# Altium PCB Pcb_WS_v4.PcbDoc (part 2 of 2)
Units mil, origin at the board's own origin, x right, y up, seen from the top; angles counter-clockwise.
Board outline 3890 x 3890 mil, 2 copper layers (Top Layer, Bottom Layer); 84 components, 65 nets, 260 pads, 399 vias.
Unrouted connection lines stored in the file: 15.

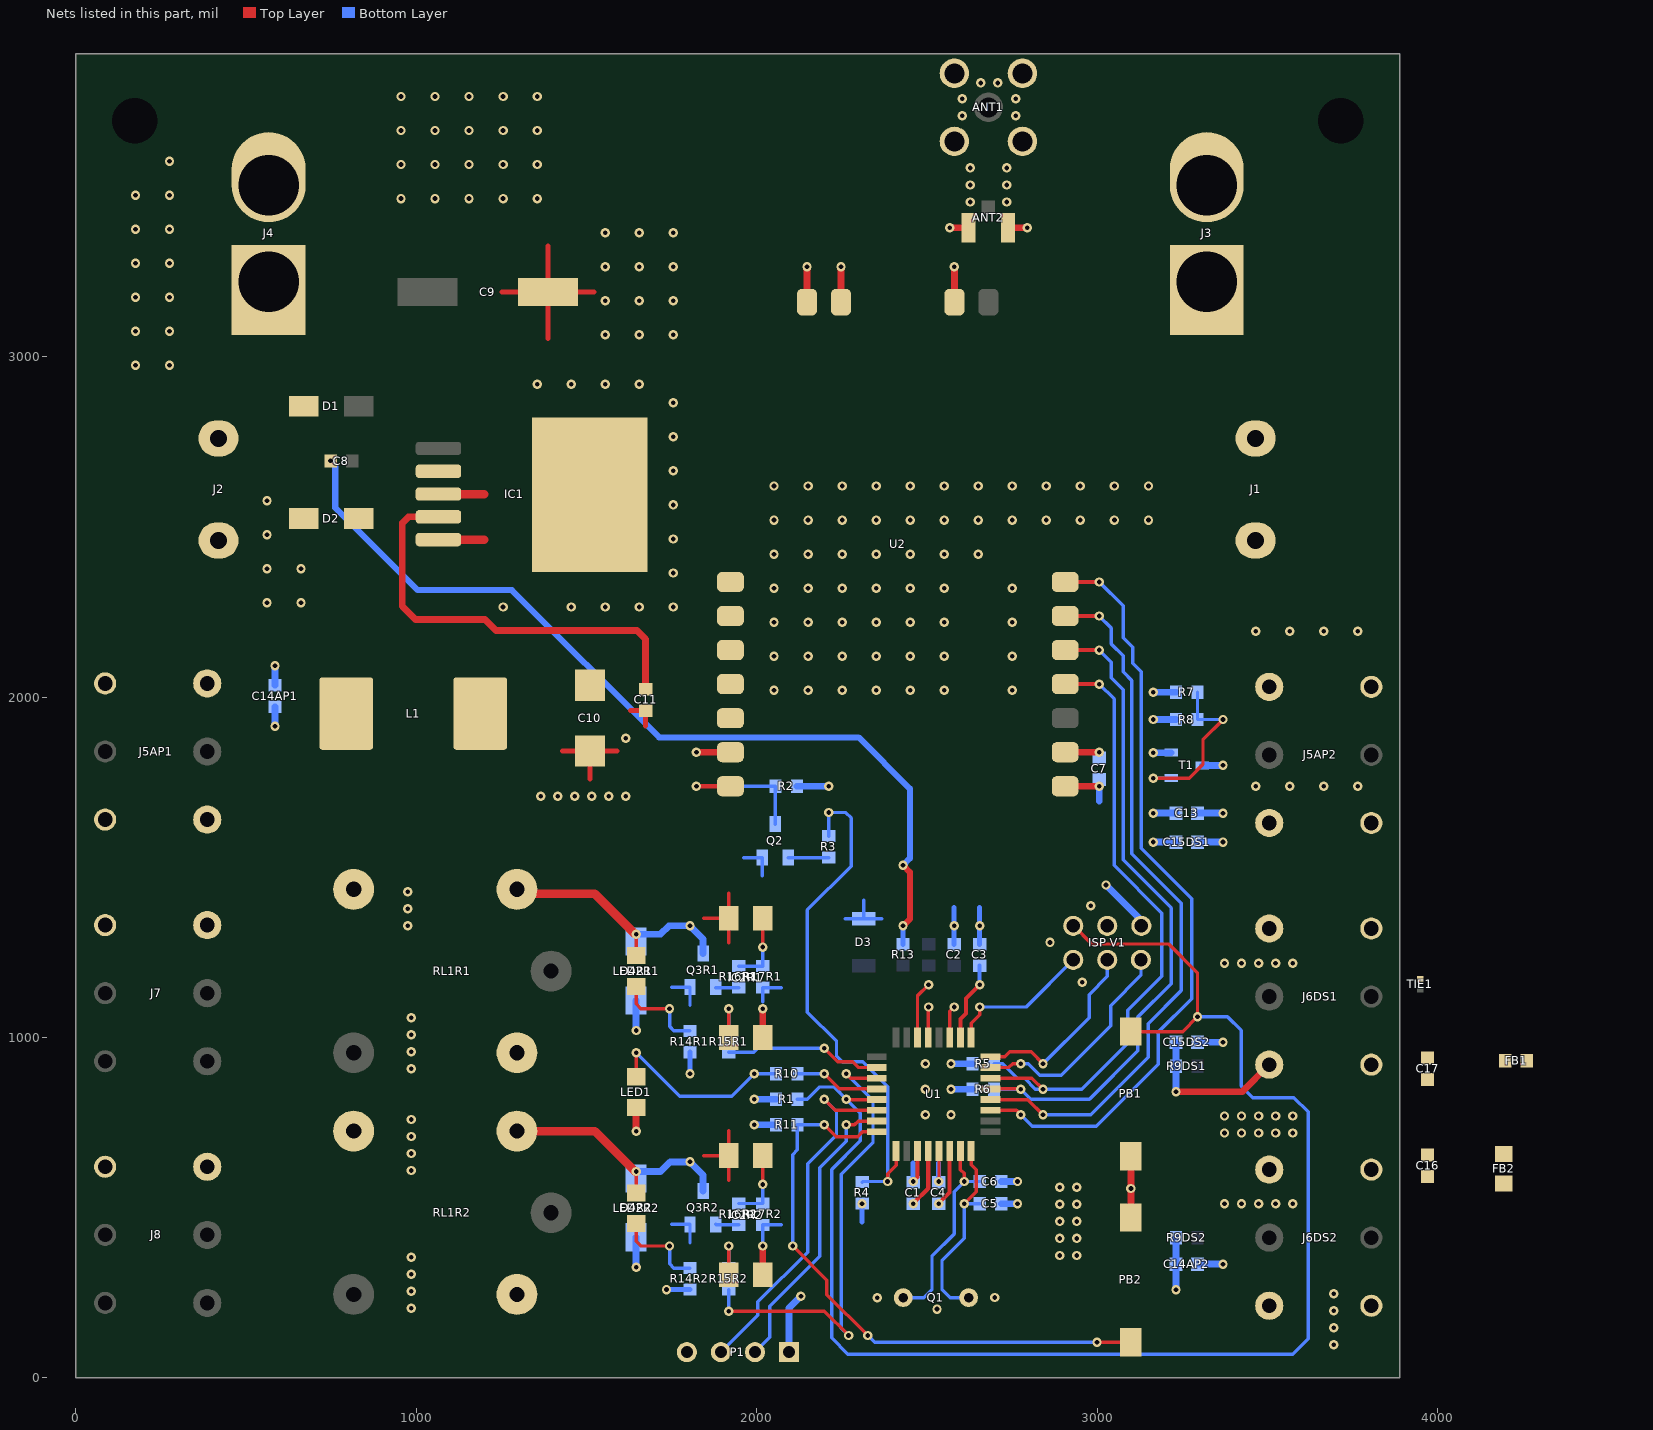
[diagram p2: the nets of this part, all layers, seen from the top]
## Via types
v1: diameter 27.56, hole 13.78, Top Layer to Bottom Layer, tented both sides, 321 vias
v2: diameter 20, hole 11.81, Top Layer to Bottom Layer, tented both sides, 76 vias
v3: diameter 27.56, hole 13.78, Top Layer to Bottom Layer, tented top, 2 vias

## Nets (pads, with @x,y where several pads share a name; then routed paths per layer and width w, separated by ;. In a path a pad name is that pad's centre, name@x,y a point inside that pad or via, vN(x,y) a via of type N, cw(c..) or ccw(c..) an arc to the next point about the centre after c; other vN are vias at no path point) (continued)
GND: "ISP V1.5" C1.2 C2.1 C3.2 C4.2 C5.2 C6.2 C7.1 C8.2 C9.2 C10.2 C11.2 C13.2 C14AP1.1 C14AP2.1 C15DS1.1 C15DS2.1 C16.1 C17.1 D2.2 D3.2 IC1.3 IC1.5 IC1.6 IC2R1.2 IC2R2.2 J2.1 J4.1 J5AP1.3 J5AP2.3 J6DS1.3 J6DS2.3 LED1.2 P1.4 PB1.2 PB2.2 Q2.2 Q3R1.2 Q3R2.2 R4.1 R5.2 R6.2 R7.1 R13.2 R17R1.1 R17R2.1 TIE1.1 U1.3 U1.5 U1.21 U2.7 U2.9 | length 6440.5
  Top Layer w9.84: U1.21@2504.06,1000.59 2504.06,1089.06 v1(2505,1090) ; v1(2534.61,577.18) 2535.55,578.13 U1.5@2535.55,666.59
  Top Layer w12: v1(2459.61,577.18) 2472.56,590.13 U1.3@2472.56,666.59
  Top Layer w15: 1251.93,3190 C9.2@1387.17,3190 ; 1387.17,3054.77 C9.2@1387.17,3190 ; 1387.17,3325.23 C9.2@1387.17,3190 ; 1430,1842.04 C10.2@1510,1842.04 1590,1842.04 ; 1510.45,1759.93 C10.2@1510.45,1839.93 ; 1522.4,3190 C9.2@1387.17,3190 ; 1629.05,1960.5 C11.2@1673.55,1960.5 1673.55,1916
  Top Layer w18: v1(2430,1328.39) 2450,1348.39 2450,1377.69 2450,1486 v1(2430,1506)
  Top Layer w20: v1(1645.86,724.46) LED1.2@1645.86,795 ; v1(1822.96,1838.49) U2.9@1922.96,1838.49 ; IC2R2.2@2017.86,303.06 v1(2017.86,387.87) ; IC2R1.2@2017.86,1000.34 v1(2017.86,1085.15) ; U2.7@2906.43,1738.49 v3(3006.43,1738.49) ; PB2.2@3099.53,471.14 v1(3099.53,556.63) PB1.2@3099.53,651.54
  Top Layer w25: IC1.5@1065.04,2463.1 1200.27,2463.1 ; IC1.3@1065.04,2596.96 1200.27,2596.96
  Bottom Layer w10: 1750.16,451.1 Q3R2.2@1804.06,451.1 1804.06,397.2 ; 1750.16,1148.38 Q3R1.2@1804.06,1148.38 1804.06,1094.48 ; 1962.5,1528.58 Q2.2@2016.4,1528.58 2016.4,1474.68 ; v1(2017.86,387.87) R17R2.1@2017.86,449.74 2071.76,449.74 ; 2017.86,1105.65 R17R1.1@2017.86,1147.02 2071.76,1147.02 ; 2260.17,1349.12 D3.2@2314.07,1349.12 ; 2314.07,1403.02 D3.2@2314.07,1349.12 ; 2367.98,1349.12 D3.2@2314.07,1349.12
  Bottom Layer w15: 2309.61,458.28 v1(2309.61,512.18) ; R13.2@2430,1274.31 v1(2430,1328.39) ; v1(2459.61,577.18) 2459.61,631.08 ; v1(2534.61,577.18) 2534.61,631.08 ; C2.1@2580,1274.31 v1(2580,1328.39) 2580,1382.47 ; C3.2@2655,1274.31 v1(2655,1328.39) 2655,1382.47
  Bottom Layer w18: v1(748,2694.78) 748,2693.46 762,2679.46 762,2556.74 1003.74,2315 1280.5,2315 1713.5,1882 2299.33,1882 2450,1731.33 2450,1526.7 2430,1506.7 v1(2430,1506)
  Bottom Layer w20: C14AP1.1@585,2035 v1(585,2092.32) ; v1(2570.81,848.39) R6.2@2634.67,848.39 ; v1(2570.81,923.39) R5.2@2634.67,923.39 ; C5.2@2718.3,512.18 v1(2766.21,512.18) ; C6.2@2718.3,577.18 v1(2766.21,577.18) ; 3006.43,1695 v3(3006.43,1738.49) ; v1(3165,1574.46) C15DS1.1@3232.01,1574.46 ; v1(3165,1659.46) C13.2@3232.01,1659.46 ; v1(3165,2014.46) R7.1@3232.01,2014.46 ; C14AP2.1@3295,334.46 v1(3370,334.46) ; C15DS2.1@3295,986.31 v1(3370,986.31)
  other v1: 2529.75,202.52 985,205 2353.96,235.91 2699.14,236.33 985,255 985,305 985,355 2890.32,360.02 2940.32,360.02 2890.32,410.02 2940.32,410.02 2890.32,460.02 2940.32,460.02 2890.32,510.02 2940.32,510.02 3374.51,512.18 3424.51,512.18 3474.51,512.18 3524.51,512.18 3574.51,512.18 2890.32,560.02 2940.32,560.02 985,609.51 985,659.51 985,709.51 3374.51,719.61 3424.51,719.61 3474.51,719.61 3524.51,719.61 3574.51,719.61 985,759.51 3374.51,769.61 3424.51,769.61 3474.51,769.61 3524.51,769.61 3574.51,769.61 2495.81,773.39 2570.81,773.39 2495.81,848.39 985,908.21 2495.81,923.39 985,958.21 985,1008.21 985,1058.21 2956.35,1162.33 3374.51,1218.65 3424.51,1218.65 3474.51,1218.65 3524.51,1218.65 3574.51,1218.65 2861.6,1279.69 975,1328.39 975,1378.39 2981.3,1387.43 975,1428.39 1365.62,1708.72 1415.62,1708.72 1465.62,1708.72 1515.62,1708.72 1565.62,1708.72 1615.62,1708.72 3465.86,1738.49 3565.86,1738.49 3665.86,1738.49 3765.86,1738.49 1615.62,1879.25 2051.06,2020.48 2151.06,2020.48 2251.06,2020.48 2351.06,2020.48 2451.06,2020.48 2551.06,2020.48 2751.06,2020.48 2051.06,2120.48 2151.06,2120.48 2251.06,2120.48 2351.06,2120.48 2451.06,2120.48 2551.06,2120.48 2751.06,2120.48 3465.86,2193.71 3565.86,2193.71 3665.86,2193.71 3765.86,2193.71 2051.06,2220.48 2151.06,2220.48 2251.06,2220.48 2351.06,2220.48 2451.06,2220.48 2551.06,2220.48 2751.06,2220.48 1255,2265 1455,2265 1555,2265 1655,2265 1755,2265 561.41,2277.57 661.41,2277.57 2051.06,2320.48 2151.06,2320.48 2251.06,2320.48 2351.06,2320.48 2451.06,2320.48 2551.06,2320.48 2751.06,2320.48 1755,2365 561.41,2377.57 661.41,2377.57 2051.06,2420.48 2151.06,2420.48 2251.06,2420.48 2351.06,2420.48 2451.06,2420.48 2551.06,2420.48 2651.06,2420.48 1755,2465 561.41,2477.57 2051.06,2520.48 2151.06,2520.48 2251.06,2520.48 2351.06,2520.48 2451.06,2520.48 2551.06,2520.48 2651.06,2520.48 2751.06,2520.48 2851.06,2520.48 2951.06,2520.48 3051.06,2520.48 3151.06,2520.48 1755,2565 561.41,2577.57 2051.06,2620.48 2151.06,2620.48 2251.06,2620.48 2351.06,2620.48 2451.06,2620.48 2551.06,2620.48 2651.06,2620.48 2751.06,2620.48 2851.06,2620.48 2951.06,2620.48 3051.06,2620.48 3151.06,2620.48 1755,2665 1755,2765 1755,2865 1355,2919.51 1455,2919.51 1555,2919.51 1655,2919.51 175,2975 275,2975 1555,3065 1655,3065 1755,3065 175,3075 275,3075 1555,3165 1655,3165 1755,3165 175,3175 275,3175 1555,3265 1655,3265 1755,3265 175,3275 275,3275 1555,3365 1655,3365 1755,3365 175,3375 275,3375 955,3465 1055,3465 1155,3465 1255,3465 1355,3465 175,3475 275,3475 955,3565 1055,3565 1155,3565 1255,3565 1355,3565 275,3575 955,3665 1055,3665 1155,3665 1255,3665 1355,3665 955,3765 1055,3765 1155,3765 1255,3765 1355,3765
GND-SOLAR: J1.2 J3.1
GND_ANT: ANT1.2 ANT2.2 U2.15 U2.16 U2.17 | length 425.1
  Top Layer w20: U2.15@2147.76,3160.54 v1(2147.76,3265) ; U2.16@2247.76,3160.54 v1(2247.76,3265) ; v1(2566.92,3379) ANT2.2@2622.76,3379 ; U2.17@2580.84,3160.54 v1(2580.84,3265) ; ANT2.2@2738.91,3379 v1(2794.75,3379)
  other v1: 2627.07,3455 2734.27,3455 2627.07,3505 2734.27,3505 2627.07,3555 2734.27,3555 2604.38,3708.09 2761.22,3708.09 2604.38,3758.09 2761.22,3758.09 2658.24,3804.81 2708.24,3804.81
LED: R10.1 U1.28 | length 251.5
  Top Layer w10: v1(2198.39,893.79) 2242.84,849.34 U1.28@2352.8,849.34
  Bottom Layer w10: R10.1@2119.71,893.79 v1(2198.39,893.79)
M0: U1.11 U2.1 | length 2257
  Top Layer w10: U1.11@2686.8,786.35 2763.26,786.35 v1(2776.21,773.39)
  Top Layer w12: U2.1@2906.43,2338.49 v1(3006.43,2338.49)
  Bottom Layer w10: v1(2776.21,773.39) 2809.61,740 2997.76,740 3180,922.24 3180,1016.44 3277.78,1114.22 3277.78,1408.22 3130,1556 3130,2074.32 3104.99,2099.33 3104.99,2146.3 3076.66,2174.62 3076.66,2268.26 v1(3006.43,2338.49)
M1: U1.12 U2.2 | length 2088.2
  Top Layer w10: U1.12@2686.8,817.84 2796.76,817.84 v1(2841.21,773.39)
  Top Layer w12: U2.2@2906.43,2238.49 v1(3006.43,2238.49)
  Bottom Layer w10: v1(2841.21,773.39) 2981.3,773.39 3150,942.09 3150,1040.78 3247.63,1138.4 3247.63,1394.3 3101.84,1540.08 3101.84,2049.15 3076.66,2074.32 3076.66,2121.29 3041.54,2156.41 3041.54,2203.37 v1(3006.43,2238.49)
MISO: "ISP V1.2" U1.16 | length 558.1
  Top Layer w10: U1.16@2686.8,943.83 2728.65,943.83 2743.21,958.39 2806.21,958.39 v1(2841.21,923.39)
  Bottom Layer w10: v1(2841.21,923.39) 2976.74,1058.92 2976.74,1126.42 3030,1179.68 3030,1228.39
MOSI: "ISP V1.3" U1.15 | length 662
  Top Layer w10: U1.15@2686.8,912.33 2741.13,912.33 2752.19,923.39 v1(2776.21,923.39)
  Bottom Layer w10: v1(2776.21,923.39) 2798.31,923.39 2831.71,890 2895.12,890 3040.32,1035.19 3040.32,1094.12 3129,1182.8 3129,1228.39
NetC16_2: C16.2 FB2.2 U2.6
NetC17_2: C17.2 FB1.2 U1.18
NetD2_1: D2.1 IC1.2 L1.1
NetD4R1_2: D4R1.2 LED2R1.2 Q3R1.3 RL1R1.4 | length 728.5
  Top Layer w10: LED2R1.2@1645.86,1240.54 v1(1645.86,1303.81)
  Top Layer w25: RL1R1.4@1295.86,1422.82 1524.46,1422.82 v1@1643.47,1303.81
  Bottom Layer w20: D4R1.2@1643.47,1303.81 v1(1645.86,1303.81) 1717.53,1303.81 1742.11,1328.39 v1(1804.06,1328.39) 1842.66,1289.8 Q3R1.3@1842.66,1246.8
NetD4R2_2: D4R2.2 LED2R2.2 Q3R2.3 RL1R2.4 | length 734
  Top Layer w10: LED2R2.2@1645.86,543.26 v1(1645.86,606.53)
  Top Layer w25: RL1R2.4@1295.86,725.54 1524.46,725.54 v1@1643.47,606.53
  Bottom Layer w20: D4R2.2@1643.47,606.53 1717.53,606.53 1746,635 v1(1804.06,635) 1842.66,596.4 Q3R2.3@1842.66,549.52
NetIC2R1_1: IC2R1.1 R15R1.2 | length 149.9
  Top Layer w10: IC2R1.1@1917.86,1000.34 v1(1917.86,1085.15)
  Bottom Layer w10: R15R1.2@1917.86,1020.01 v1(1917.86,1085.15)
NetIC2R2_1: IC2R2.1 R15R2.2 | length 149.9
  Top Layer w10: IC2R2.1@1917.86,303.06 v1(1917.86,387.87)
  Bottom Layer w10: R15R2.2@1917.86,322.73 v1(1917.86,387.87)
NetLED1_1: LED1.1 R10.2 | length 561.5
  Top Layer w10: LED1.1@1645.86,885 v1(1645.86,955.54)
  Bottom Layer w10: v1(1645.86,955.54) 1773.4,828 1927.07,828 v1(1992.86,893.79) R10.2@2056.72,893.79
NetLED2R1_1: LED2R1.1 R14R1.2 | length 273.2
  Top Layer w10: LED2R1.1@1645.86,1150.54 1645.86,1099.14 1659.86,1085.14 v1(1744.06,1085.14)
  Bottom Layer w10: v1(1744.06,1085.14) 1744.06,1032.6 1756.65,1020.01 R14R1.2@1804.06,1020.01
NetLED2R2_1: LED2R2.1 R14R2.2 | length 273.2
  Top Layer w10: LED2R2.1@1645.86,453.26 1645.86,401.86 1659.86,387.87 v1(1744.06,387.87)
  Bottom Layer w10: v1(1744.06,387.87) 1744.06,335.32 1756.65,322.73 R14R2.2@1804.06,322.73
NetQ2_1: Q2.1 R3.2 | length 119.9
  Bottom Layer w10: Q2.1@2092.2,1528.8 R3.2@2212.06,1528.8
NetQ3R1_1: Q3R1.1 R16R1.2 | length 68.4
  Bottom Layer w10: Q3R1.1@1879.86,1146.01 1946.85,1146.01 R16R1.2@1947.86,1147.02
NetQ3R2_1: Q3R2.1 R16R2.2 | length 68.7
  Bottom Layer w10: Q3R2.1@1879.86,451.31 1881.43,449.74 R16R2.2@1947.86,449.74
NetR7_2: R7.2 R8.2 T1.1 | length 527.4
  Top Layer w10: v1(3165,1762.33) 3271.14,1762.33 3311.13,1802.32 3311.13,1875.59 v1(3370,1934.46)
  Bottom Layer w10: v1(3165,1762.33) T1.1@3218.23,1762.33 ; R7.2@3295,2014.46 R8.2@3295,1934.46 v1(3370,1934.46)
NetU1_19: U1.19 | length 94.8
  Top Layer w10: U1.19@2567.05,1000.59 2567.05,1077.05 v1(2580,1090)
NetU1_22: U1.22 | length 167.8
  Top Layer w10: U1.22@2472.56,1000.59 2472.56,1122.56 v1(2505,1155)
NetU2_10: U2.10
NetU2_11: U2.11
NetU2_12: U2.12
NetU2_13: U2.13
NetU2_14: U2.14
OPEN1: J7.1 RL1R1.3
OPEN2: J8.1 RL1R2.3
P5V-Main: "ISP V1.6" C1.1 C3.1 C4.1 C7.2 C10.1 C11.1 D4R1.1 D4R2.1 FB1.1 FB2.1 IC1.4 IC2R1.4 IC2R2.4 L1.2 P1.1 R1.1 R2.2 R8.1 R11.1 R14R1.1 R14R2.1 RL1R1.5 RL1R2.5 T1.2 U1.4 U1.6 | length 3364.2
  Top Layer w10: 1845,653.46 IC2R2.4@1917.86,653.46 ; 1845,1350.74 IC2R1.4@1917.86,1350.74 ; 1917.86,580.6 IC2R2.4@1917.86,653.46 ; 1917.86,726.32 IC2R2.4@1917.86,653.46 ; 1917.86,1277.88 IC2R1.4@1917.86,1350.74 ; 1917.86,1423.59 IC2R1.4@1917.86,1350.74
  Top Layer w12: v1(2459.61,512.18) 2504.06,556.63 U1.4@2504.06,666.59 ; v1(2534.61,512.18) 2567.05,544.62 U1.6@2567.05,666.59 ; 2598.54,1000.59 2598.54,1054.92 2615,1071.38 2615,1115 v1(2655,1155)
  Top Layer w20: IC1.4@1065.04,2530.03 977.03,2530.03 959,2512 959,2267.02 998.02,2228 1202,2228 1234.23,2195.77 1648.39,2195.77 1673.55,2170.61 C11.1@1673.55,2023.5 ; 2906.43,1838.49 v3(3006.43,1838.49)
  Bottom Layer w12: v1(2655,1155) C3.1@2655,1211.32
  Bottom Layer w15: v1(1735,259.74) R14R2.1@1804.06,259.74 ; v1(1804.06,893.79) R14R1.1@1804.06,957.02
  Bottom Layer w20: v1(1645.86,325.47) D4R2.1@1645.86,413.39 ; v1(1645.86,1021.01) D4R1.1@1645.86,1108.93 ; v1(1992.86,743.79) R11.1@2056.72,743.79 ; v1(1992.86,818.79) R1.1@2056.72,818.79 ; P1.1@2095,76 2095,205.55 v1(2130,240.55) ; R2.2@2117.99,1738.49 v1(2212.06,1738.49) ; v1(3026.21,1448.39) 3130,1344.6 3130,1328.39 ; v1(3165,1837.14) T1.2@3218.23,1837.14 ; v1(3165,1934.46) R8.1@3232.01,1934.46
P5V-SEN: C13.1 C14AP1.2 C14AP2.2 C15DS1.2 C15DS2.2 J5AP1.1 J5AP2.1 J6DS1.1 J6DS2.1 R9DS1.2 R9DS2.2 T1.3 | length 873.8
  Top Layer w20: v1(3232.01,840.77) 3426.09,840.77 J6DS1.1@3505.86,920.54
  Bottom Layer w20: v1(585,1914.69) C14AP1.2@585,1972.01 ; v1(3232.01,259.46) C14AP2.2@3232.01,334.46 R9DS2.2@3232.01,412.26 ; v1(3232.01,840.77) R9DS1.2@3232.01,915.77 C15DS2.2@3232.01,986.31 ; C15DS1.2@3295,1574.46 v1(3370,1574.46) ; C13.1@3295,1659.46 v1(3370,1659.46) ; T1.3@3308.78,1799.74 v1(3370,1799.74)
  other v1: 3695,97.74 3695,147.74 3695,197.74 3695,247.74
P12V-BAT: D1.2 J2.2 J4.2
P16V-SOLAR: J1.1 J3.2
RESET-E32: R3.1 R4.2 U1.1 | length 1571.2
  Top Layer w10: v1(2384.61,577.18) 2384.61,599.79 2409.57,624.75 U1.1@2409.57,666.59
  Bottom Layer w9.84: R3.1@2212.06,1591.79 v1(2212.06,1661.26)
  Bottom Layer w10: v1(2212.06,1661.26) 2261.59,1661.26 2277.53,1645.32 2277.53,1503.75 2148.79,1375.01 2148.79,1074.97 2234.61,989.15 2234.61,945.77 2251.6,928.79 2311.16,928.79 2384.61,855.34 v1(2384.61,577.18) 2311.61,577.18 R4.2@2309.61,575.17
RL-CT-QR1: IC2R1.3 R16R1.1 R17R1.2 | length 210.7
  Top Layer w10: v1(2017.86,1265.93) IC2R1.3@2017.86,1350.74
  Bottom Layer w10: R16R1.1@1947.86,1210.01 R17R1.2@2017.86,1210.01 v1(2017.86,1265.93)
RL-CT-QR2: IC2R2.3 R16R2.1 R17R2.2 | length 210.7
  Top Layer w10: v1(2017.86,568.65) IC2R2.3@2017.86,653.46
  Bottom Layer w10: R16R2.1@1947.86,512.73 R17R2.2@2017.86,512.73 v1(2017.86,568.65)
RL-CTL1: R15R1.1 U1.26 | length 463.2
  Top Layer w10: v1(2198.39,968.79) 2238.39,928.79 2282.02,928.79 2298.48,912.33 U1.26@2352.8,912.33
  Bottom Layer w10: R15R1.1@1917.86,957.02 1991.67,957.02 2003.44,968.79 v1(2198.39,968.79)
RL-CTL2: R15R2.1 U1.27 | length 1388.2
  Top Layer w10: v1(1917.86,196.51) 2198.49,196.51 v1(2270,125) ; v1(2263.39,893.79) 2276.35,880.83 U1.27@2352.8,880.83
  Bottom Layer w10: v1(1917.86,196.51) R15R2.1@1917.86,259.74 ; v1(2263.39,893.79) 2341.63,815.55 2341.63,691.63 2248.78,598.78 2248.78,146.22 v1(2270,125)
RST-E32: Q2.3 R2.1 U2.8 | length 443.5
  Top Layer w12: v1(1822.96,1738.49) U2.8@1922.96,1738.49
  Bottom Layer w10: v1(1822.96,1738.49) R2.1@2055,1738.49 Q2.3@2055,1627.01
RST_MCU: "ISP V1.4" PB1.1 R1.2 U1.29 | length 4423.1
  Top Layer w10: v1(2263.39,818.79) 2264.34,817.84 U1.29@2352.8,817.84 ; 2930,1328.39 2931.61,1328.39 2985,1275 3210,1275 3295,1190 v1(3295,1061.31) 3251.37,1017.69 PB1.1@3099.53,1017.69
  Bottom Layer w10: R1.2@2119.71,818.79 2148.79,818.79 2185,855 2227.18,855 v1(2263.39,818.79) 2304.79,777.39 2304.79,697.4 2220,612.61 2220,117.62 2267.62,70 3574.61,70 3620.17,115.57 3620.17,781.82 3578.32,823.68 3457.64,823.68 3423.54,857.78 3423.54,1021 3383.22,1061.31 v1(3295,1061.31)
RXD-E32: R6.1 U1.13 U2.3 | length 1989.3
  Top Layer w10: U1.13@2686.8,849.34 2775.27,849.34 v1(2776.21,848.39)
  Top Layer w12: U2.3@2906.43,2138.49 v1(3006.43,2138.49)
  Bottom Layer w10: R6.1@2697.66,848.39 v1(2776.21,848.39) 2805.82,818.79 2977.86,818.79 3120,960.92 3120,1060.54 3218.23,1158.77 3218.23,1380.88 3076.66,1522.45 3076.66,2022.11 3041.54,2057.22 3041.54,2103.37 v1(3006.43,2138.49)
RXM: P1.3 U1.30 | length 1066.3
  Top Layer w10: v1(2198.39,818.79) 2230.83,786.35 U1.30@2352.8,786.35
  Bottom Layer w10: P1.3@1895,76 2003.44,184.44 2003.44,223.44 2150,370 2150,630 2234.61,714.61 2234.61,782.57 v1(2198.39,818.79)
SCK: "ISP V1.1" U1.17 | length 432.1
  Top Layer w10: U1.17@2630.04,1000.59 2630.04,1042.43 2655,1067.39 v1(2655,1090)
  Bottom Layer w10: v1(2655,1090) 2791.61,1090 2930,1228.39
TXD-E32: R5.1 U1.14 U2.4 | length 1919.5
  Top Layer w10: U1.14@2686.8,880.83 2808.77,880.83 v1(2841.21,848.39)
  Top Layer w12: U2.4@2906.43,2038.49 v1(3006.43,2038.49)
  Bottom Layer w10: R5.1@2697.66,923.39 2722.59,923.39 2765.98,880 2787.28,880 2818.89,848.39 v1(2841.21,848.39) 2954.61,848.39 3090,983.79 3090,1080 3190,1180 3190,1366 3050,1506 3050,1994.92 v1(3006.43,2038.49)
TXM: P1.2 U1.31 | length 873
  Top Layer w10: v1(2263.39,743.79) 2287.41,743.79 2298.48,754.85 U1.31@2352.8,754.85
  Bottom Layer w10: P1.2@1995,76 2038.25,119.25 2038.25,211.2 2185,357.95 2185,617.5 2263.39,695.89 v1(2263.39,743.79)
WAKE: PB2.1 R11.2 U1.32 | length 1751
  Top Layer w10: v1(2105.83,387.87) 2206.2,287.5 2206.2,245.15 v1(2326.35,125) ; v1(2198.39,743.79) 2233.39,708.79 2296.39,708.79 2310.96,723.35 U1.32@2352.8,723.35 ; v1(3000,105) PB2.1@3099.53,105
  Bottom Layer w10: v1(2105.83,387.87) 2105.83,656.12 2119.71,670 R11.2@2119.71,743.79 v1(2198.39,743.79) ; v1(2326.35,125) 2327.05,125 2347.05,105 v1(3000,105)
XTAL1: C6.1 Q1.1 U1.7 | length 590.6
  Top Layer w10: U1.7@2598.54,666.59 2598.54,612.26 2609.61,601.2 v1(2609.61,577.18)
  Bottom Layer w8: v1(2609.61,577.18) C6.1@2655.31,577.18
  Bottom Layer w10: Q1.1@2430.49,236.12 2491.32,236.12 2514.95,259.74 2514.95,358.04 2580,423.09 2580,547.57 v1(2609.61,577.18)
XTAL2: C5.1 Q1.2 U1.8 | length 587.9
  Top Layer w10: v1(2609.61,512.18) 2644.61,547.18 2644.61,612.26 2630.04,626.83 U1.8@2630.04,666.59
  Bottom Layer w10: Q1.2@2622.61,236.12 2568.17,236.12 2544.55,259.74 2544.55,345.77 2609.61,410.83 v1(2609.61,512.18) C5.1@2655.31,512.18
pads on no net: HOLE1.1 HOLE2.1

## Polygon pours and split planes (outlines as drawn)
P5V-Main on Top Layer "P5V-MAIN_L01_P035" (solid, pour order 35): 1730.29,1954.85 1730.29,2120 1842.96,2120 1842.96,1975.89 1864,1954.85 3191.79,1954.85 3191.79,1813 3101.84,1813 3101.84,1420.95 2824.07,1420.95 2824.07,1131.63 2930,1131.63 2930,620.06 2736.81,620.06 2736.81,320 2657.31,320 2430.49,320 2430.49,176.44 1187.95,176.44 1187.95,1600 1320,1600 1320,1650 1659.86,1650 1659.86,1900 1715,1900 1715,1954.85
P5V-SEN on Top Layer "P5V-SEN_L01_P031" (solid, remove dead copper, pour order 31): 2622.61,292.76 2622.61,150 2223,150 2196.56,176.44 1187.95,176.44 1187.95,1600 615.98,1600 615.98,2110 590.99,2135 80,2135 40,2095 40,1972.49 60.49,1952 448.78,1952 484.78,1916 484.78,1577.12 566.9,1495 985,1495 1055,1425 1055,60.49 2146.6,60.49 2172.09,35 2975,35 2975,160.48 3020.48,160.48 3164.52,160.48 3164.52,35 3290,35 3855,35 3855,292.76
GND on Top Layer "GND_L01_P027" (solid, remove dead copper, pour order 27): 1715,1900 1715,1992 1850,1992 1850,2675 1900,2675 1900,3855 35,3855 35,2250 650,2250 650,1650 1650,1650 1650,1900
GND on Top Layer "GND_L01_P040" (solid, pour order 40): 795,1296.63 925,1166.63 925,994.62 925,35 1055,35 1055,1495 564.28,1495 485.95,1576.25 485.95,1755 35,1755 35,1428.39 533.23,1428.39 665,1296.63
GND on Top Layer "GND_L01_P039" (solid, pour order 39): 2931.03,620.06 2737.18,620.06 2737.18,320 2985,320 3855,320 3855,2238.49 3200,2238.49 3200,2675 2000,2675 2000,1968 3191.79,1968 3191.79,1813 3101.84,1813 3101.84,1420.95 2841.21,1420.95 2841.21,1131.63 2931.03,1131.63
GND_ANT on Top Layer "GND_ANT_L01_P037" (solid, pour order 37): 2000,3829.51 2000,2775 3025,2775 3025,3829.51
GND-SOLAR on Top Layer "GND-SOLAR_L01_P028" (solid, remove dead copper, pour order 28): 3300,2775 3125,2775 3125,3855 3855,3855 3855,2310 3300,2310
no net on Top Layer "Top Layer-No Net" (solid, shelved, pour order 14): 1060.77,4984.95
no net on Top Layer "AutoNaming" (solid, shelved, pour order 22): -29.14,150.54
no net on Top Layer "AutoNaming" (solid, shelved, pour order 26): -29.14,150.54
GND on Bottom Layer "GND-Bottom" (solid, remove dead copper, pour order 38): 3432.98,1830.54 3432.98,1710 3855,1710 3855,2240 3200,2240 3200,2675 1900,2675 1900,3855 35,3855 35,35 3630,35 3630,1427 3365.37,1427 3365.37,1830.54
P5V-SEN on Bottom Layer "P5V-SEN_L02_P030" (solid, remove dead copper, pour order 30): 3365.37,1439.51 3377.88,1427 3610.35,1427 3630,1407.35 3630,336.82 3630,35 3845,35 3845,1680 3830,1695 3432.69,1695 3417.69,1710 3417.69,1830.54 3365.37,1830.54
GND_ANT on Bottom Layer "GND_ANT_L02_P033" (solid, pour order 33): 2000,3829.51 2000,2775 3025,2775 3025,3829.51
P16V-SOLAR on Bottom Layer "P16V-SOLAR_L02_P029" (solid, pour order 29): 3300,2775 3125,2775 3125,3862.5 3862.5,3862.5 3862.5,2310 3300,2310

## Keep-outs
Bottom Layer:
  region: 3864.91,2241.96
Keep-Out Layer:
  the board outline again, w5

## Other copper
Top Layer:
  pour cut-out: 2999,1868.27 cw(c2999,1860.84) 3006.43,1860.84 3006.43,1814.84 cw(c3000.3,1814.84) 3000.3,1808.72 2866.81,1808.72 2866.81,1868.27
  pour cut-out: 2515,492 ccw(c2515,501) 2524,501 2524,512 2545,512 2545,501 ccw(c2554,501) 2554,492 2609.61,492 2609.61,577.18 2370.19,577.18 2370.19,498 2384,498 2384,492 2441,492 ccw(c2441,500) 2449,500 2449,512 2470,512 2470,500 ccw(c2478,500) 2478,492
  pour cut-out: 2632.42,1175.39 cw(c2632.42,1165.81) 2642,1165.81 2642,1155 ccw(c2655,1155) 2655,1142 2667,1142 cw(c2667.2,1133.8) 2675.39,1134 2675.39,1090 2430,1090 2430,1175.39
  region net EARTH: 15,15 3875,14.82 3875,3875.04 2890,3875 2890,3855 3855,3855 3855,35 35,35 35,3855 2480,3855 2480,3875 15,3875
  pour cut-out: 3065.36,514.6 3133,514.6 3133,427.6 3065.36,427.6
  pour cut-out: 3065.36,695 3133,695 3133,608 3065.36,608
  pour cut-out: 2946.04,1768.27 2946.04,1708.72 2866.81,1708.72 2866.81,1768.27
  region net GND: 2679.54,305.26 2693.29,299.56 2705.67,291.29 2716.2,280.77 2724.47,268.39 2730.17,254.63 2733.07,240.03 2733.07,232.58 2733.07,225.83 2730.44,212.58 2725.27,200.1 2717.76,188.86 2708.21,179.31 2696.97,171.81 2684.49,166.64 2671.24,164 2387.87,164 2373.35,166.89 2359.67,172.55 2347.37,180.78 2336.9,191.24 2328.67,203.55 2323.01,217.23 2320.12,231.74 2320.12,239.15 2320.12,245.94 2322.77,259.28 2327.98,271.84 2335.53,283.14 2345.14,292.76 2356.45,300.31 2369.01,305.51 2382.35,308.17 2664.93,308.17 hole: 2622.61,274 2612.81,272.71 2603.67,268.93 2595.83,262.91 2589.81,255.06 2586.02,245.92 2584.73,236.12 2586.02,226.31 2589.81,217.18 2595.83,209.33 2603.67,203.31 2612.81,199.53 2622.61,198.24 2632.42,199.53 2641.56,203.31 2649.4,209.33 2655.42,217.18 2659.21,226.31 2660.5,236.12 2659.21,245.92 2655.42,255.06 2649.4,262.91 2641.56,268.93 2632.42,272.71 hole: 2430.49,274 2420.68,272.71 2411.55,268.93 2403.7,262.91 2397.68,255.06 2393.9,245.92 2392.61,236.12 2393.9,226.31 2397.68,217.18 2403.7,209.33 2411.55,203.31 2420.68,199.53 2430.49,198.24 2440.29,199.53 2449.43,203.31 2457.28,209.33 2463.3,217.18 2467.08,226.31 2468.37,236.12 2467.08,245.92 2463.3,255.06 2457.28,262.91 2449.43,268.93 2440.29,272.71
  region net GND: 2410,945 2410,723.35 2630.04,723.35 2630.04,943.83
  pour cut-out: 2600,3425 2761.22,3425 2761.22,3334.04 2600,3334.04
  pour cut-out: 2551.06,3200.16 2610.61,3200.16 2610.61,3120.92 2551.06,3120.92
  pour cut-out: 2217.99,3200.16 2277.54,3200.16 2277.54,3120.92 2217.99,3120.92
  pour cut-out: 2117.99,3200.16 2177.54,3200.16 2177.54,3120.92 2117.99,3120.92
  pour cut-out: 2905,1880
  pour cut-out: 2905,1880
  pour cut-out: 2384.57,968.83 2655.04,968.83 2655.04,698.35 2384.57,698.35
  pour cut-out: 1874.31,354.48 2061.4,354.48 2061.4,251.65 1874.31,251.65
  pour cut-out: 2061.4,1402.15 2061.4,1299.32 1880,1299.32 1880,1402.15
  pour cut-out: 1603.36,1280.54 1688.36,1280.54 1688.36,1110.54 1603.36,1110.54
  pour cut-out: 1603.36,925 1688.36,925 1688.36,755 1603.36,755
  pour cut-out: 1688.36,583.26 1603.36,583.26 1603.36,413.26 1688.36,413.26
  pour cut-out: 2061.4,602.04 2061.4,704.87 1880,704.87 1880,602.04
  pour cut-out: 2178,743.79 2178,968.79 2183.97,968.79 2183.97,983.21 2263.39,983.21 2263.39,743.79
  pour cut-out: 2855,698.39 2861.6,698.39 2861.6,923.39 2776.21,923.39 2776.21,683.97 2855,683.97
  pour cut-out: 2384.57,968.83
  region net BAT-VSEN: 785,2672.5 794.5,2663 905,2663 952,2710 1127.5,2710 1140,2722.5 1140,3242.01 1117.01,3265 853.72,3265 785,3196.28 785,2945 759.51,2919.51 759.51,2787.55 785,2762.06
  region net P12V-BAT: 290,2869.68 385.86,2965.54 385.86,3302.68 419.18,3336 717.06,3336 759.51,3293.55 759.51,2968.37 732.5,2941.36 732.5,2790.64 708.42,2766.55 605.99,2766.55 561.41,2721.98 561.41,2664.22 530.56,2633.38 331.95,2633.38 290,2675.33
  pour cut-out: 880,2182 1100,2182 1320,2182 1320,1650 690,1650 690,2182
  pour cut-out: 777.2,2411.28 777.2,2760 1165.49,2760 1165.49,2411.28
  region net P5V-Main: 1100,1840 1120,1820 1200,1820 1320,1820 1360,1860 1360,1940 1390,1970 1430,1970 1580,1970 1610,2000 1832.96,2000 1842.96,2010 1842.96,2110 1832.96,2120 1157.5,2120 1100,2062.5 1100,2040.54
  region net NetD2_1: 957,2685 1126,2685 1133.75,2677.25 1133.75,2649.75 1127,2643 988,2643 926,2581 926,2228 880,2182 880,1850 865,1835 715,1835 690,1860 690,2230.55 775,2315.55 775,2623.75 794.25,2643 915,2643
  region: 0,3890
  region: 982.01,1106.11
  pour cut-out: 3920.54,1420.95
  pour cut-out: 3920.54,1420.95
  region: 310.86,2890.54
Bottom Layer:
  region net EARTH: 15,15 3875,14.82 3875,3875.04 2890,3875 2890,3855 3855,3855 3855,35 35,35 35,3855 2480,3855 2480,3875 15,3875
  pour cut-out: 3199.29,446.95 3327.72,446.95 3327.72,299.78 3198.31,299.78
  pour cut-out: 550.31,2068.7 550.31,1950 615.98,1950 615.98,2068.7
  pour cut-out: 2621.61,611.86 2621.61,477.49 2791.4,477.49 2791.4,611.86
  pour cut-out: 2024,968.79 2152.42,968.79 2152.43,709.1 2024,709.1
  pour cut-out: 2971.74,1714.94 3029.61,1714.94 3029.61,1857.64 2971.74,1857.64
  pour cut-out: 650,1500 923.39,1500 923.39,1265.93 1460,1265.93 1460,1120 935,1120 935,555.93 1460,555.93 1460,410 935,410 935,35 35,35 35,1410 650,1410
  pour cut-out: 2730.38,813.71 2545.32,813.71 2545.32,958.08 2730.38,958.08
  pour cut-out: 2689.68,1177.62 2689.68,1349.59 2395.32,1349.59 2395.32,1177.62
  pour cut-out: 2358.52,1319.43 2269.69,1319.43 2269.69,1380.88 2358.52,1380.88
  pour cut-out: 2052.54,1114.3 1982.54,1114.3 1982.54,1242.73 2052.54,1242.73
  pour cut-out: 1830.79,1155 1830.79,1109.97 1777.33,1109.97 1777.33,1182 1830.79,1182
  pour cut-out: 3200.39,881.09 3327.72,881.09 3327.72,1021 3200.39,1021
  pour cut-out: 2045,1540 2045,1490.17 1989.67,1490.17 1989.67,1562.2 2045,1562.2
  pour cut-out: 1830.79,489.93 1830.79,412.69 1777.33,412.69 1777.33,489.93
  pour cut-out: 2052.54,545.45 2052.54,417.02 1982.54,417.02 1982.54,545.45
  pour cut-out: 3324.51,1694.15 3324.51,1539.78 3150.39,1539.78 3150.39,1694.15
  pour cut-out: 3327.72,2049.15 3327.72,1899.78 3150.39,1899.78 3150.39,2049.15
  pour cut-out: 2564.29,478.48 2267.62,478.48 2267.62,603.87 2564.29,603.87
  region net CLOSE1: 675,990 725,1040 887.6,1040 900,1027.6 900,890 890,880 59,880 46.49,892.51 46.49,980 56.49,990
  region net OPEN1: 58,1410 550,1410 640,1500 890,1500 900,1490 900,1360 890,1350 650,1350 570,1270 58,1270 47,1281 47,1399
  region net COM1: 55.75,1190 603.57,1190 679.51,1265.93 1440.87,1265.93 1460,1246.8 1460,1133.54 1446.46,1120 688.57,1120 638.57,1070 60,1070 45,1085 45,1179.25
  region net COM2: 55.75,480 603.57,480 679.51,555.93 1440.87,555.93 1460,536.8 1460,423.54 1446.46,410 688.57,410 638.57,360 60,360 45,375 45,469.25
  region net OPEN2: 58,700 550,700 650,800 890,800 900,790 900,650 890,640 650,640 570,560 58,560 47,571 47,689
  region net CLOSE2: 675,280 725,330 887.6,330 900,317.6 900,180 890,170 59,170 46.49,182.51 46.49,270 56.49,280
Multi-Layer:
  pour cut-out: 2480,3855 35,3855 35,35 3855,35 3855,3855 2890,3855 2890,3829.51 3829.51,3829.51 3829.51,60.49 60.49,60.49 60.49,3829.51 2480,3829.51
  pour cut-out: 1850.99,3855 2000,3855 2000,2775 3025,2775 3025,2675 1850.99,2675
  pour cut-out: 1900,2675 1850,2675 1850,2145.49 2000,2145.49 2000,2675
  pour cut-out: 35,2250 690,2250 690,1650 1466.2,1650 1466.2,1600 615.98,1600 615.98,2200 35,2200
  pour cut-out: 3855,2310 3855,2240 3200,2240 3200,2675 3025,2675 3025,3855 3125,3855 3125,2775 3300,2775 3300,2310

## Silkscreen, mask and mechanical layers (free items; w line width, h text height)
Top Overlay:
  drawing of 802 lines, arcs and shapes, not listed
  text "-" at 453.14,3701.01 h393.7
  text "-" at 3209.05,3701.01 h393.7
  text "SENSOR NODE / V3.1" at 1830,3617 h47.24
  text "FEMALE" at 765,3540 h70.87 r270
  text "FEMALE" at 3112.5,3125 h70.87 r90
  text "+BAT" at 310,2930 h120
  text "+SOLAR" at 3442.39,2920 h118.11
  text "+" at 614.07,2728.34 h196.85 r90
  text "+" at 3380.32,2715 h196.85 r90
  text "-" at 3365,2390 h275.59 r90
  text "-" at 614.07,2324.23 h275.59 r90
  text "-" at 455,2170 h275.59 r90
Bottom Overlay:
  drawing of 806 lines, arcs and shapes, not listed
  text "SN:" at 2940,2900 h60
